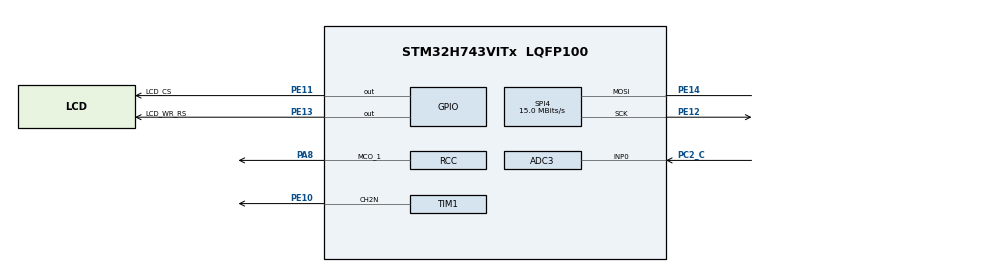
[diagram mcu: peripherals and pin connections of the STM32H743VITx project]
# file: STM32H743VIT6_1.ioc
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ADC3.Channel-0\#ChannelRegularConversion=ADC_CHANNEL_0
ADC3.NbrOfConversionFlag=1
ADC3.OffsetNumber-0\#ChannelRegularConversion=ADC_OFFSET_NONE
ADC3.OffsetSignedSaturation-0\#ChannelRegularConversion=DISABLE
ADC3.Rank-0\#ChannelRegularConversion=1
ADC3.SamplingTime-0\#ChannelRegularConversion=ADC_SAMPLETIME_1CYCLE_5
CORTEX_M7.default_mode_Activation=1
Mcu.Family=STM32H7
Mcu.Name=STM32H743VITx
Mcu.Package=LQFP100
NVIC.PriorityGroup=NVIC_PRIORITYGROUP_4
PA8.Mode=Clock-out-1
PA8.Signal=RCC_MCO_1
PC14-OSC32_IN\ (OSC32_IN).Mode=LSE-External-Oscillator
PC14-OSC32_IN\ (OSC32_IN).Signal=RCC_OSC32_IN
PC15-OSC32_OUT\ (OSC32_OUT).Mode=LSE-External-Oscillator
PC15-OSC32_OUT\ (OSC32_OUT).Signal=RCC_OSC32_OUT
PC2_C.Mode=IN0-Single-Ended
PC2_C.Signal=ADC3_INP0
PE10.Mode=PWM Generation2 CH2N
PE10.Signal=TIM1_CH2N
PE11.GPIO_Label=LCD_CS
PE11.Signal=GPIO_Output
PE12.Mode=Simplex_Bidirectional_Master
PE12.Signal=SPI4_SCK
PE13.GPIO_Label=LCD_WR_RS
PE13.Signal=GPIO_Output
PE14.Mode=Simplex_Bidirectional_Master
PE14.Signal=SPI4_MOSI
PH0-OSC_IN\ (PH0).Mode=HSE-External-Oscillator
PH0-OSC_IN\ (PH0).Signal=RCC_OSC_IN
PH1-OSC_OUT\ (PH1).Mode=HSE-External-Oscillator
PH1-OSC_OUT\ (PH1).Signal=RCC_OSC_OUT
ProjectManager.HeapSize=0x200
ProjectManager.StackSize=0x400
ProjectManager.TargetToolchain=STM32CubeIDE
RCC.ADCFreq_Value=80000000
RCC.APB1Freq_Value=120000000
RCC.APB2Freq_Value=120000000
RCC.APB3Freq_Value=120000000
RCC.APB4Freq_Value=120000000
RCC.CortexFreq_Value=480000000
RCC.D1PPRE=RCC_APB3_DIV2
RCC.D2PPRE1=RCC_APB1_DIV2
RCC.D2PPRE2=RCC_APB2_DIV2
RCC.D3PPRE=RCC_APB4_DIV2
RCC.DIVM1=4
RCC.DIVM2=4
RCC.DIVN1=60
RCC.DIVN2=10
RCC.DIVQ1=5
RCC.HCLKFreq_Value=240000000
RCC.HPRE=RCC_HCLK_DIV2
RCC.PLL2FRACN=0
RCC.PLL3FRACN=0
RCC.PLLFRACN=0
RCC.SYSCLKFreq_VALUE=480000000
RCC.SYSCLKSource=RCC_SYSCLKSOURCE_PLLCLK
RCC.USBFreq_Value=192000000
SPI4.BaudRatePrescaler=SPI_BAUDRATEPRESCALER_8
SPI4.CalculateBaudRate=15.0 MBits/s
SPI4.DataSize=SPI_DATASIZE_8BIT
SPI4.Direction=SPI_DIRECTION_1LINE
SPI4.Mode=SPI_MODE_MASTER
SPI4.VirtualType=VM_MASTER
TIM1.Channel-PWM\ Generation2\ CH2N=TIM_CHANNEL_2
VP_MEMORYMAP_VS_MEMORYMAP.Mode=CurAppReg
board=custom

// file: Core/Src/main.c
/* USER CODE BEGIN Header */
/**
  ******************************************************************************
  * @file           : main.c
  * @brief          : Main program body
  ******************************************************************************
  * @attention
  *
  * Copyright (c) 2026 STMicroelectronics.
  * All rights reserved.
  *
  * This software is licensed under terms that can be found in the LICENSE file
  * in the root directory of this software component.
  * If no LICENSE file comes with this software, it is provided AS-IS.
  *
  ******************************************************************************
  */
/* USER CODE END Header */
#include "main.h"

/* USER CODE BEGIN Includes */
#include "st7735.h"
/* USER CODE END Includes */

ADC_HandleTypeDef hadc3;

SPI_HandleTypeDef hspi4;

TIM_HandleTypeDef htim1;

void SystemClock_Config(void);
static void MPU_Config(void);
static void MX_GPIO_Init(void);
static void MX_ADC3_Init(void);
static void MX_SPI4_Init(void);
static void MX_TIM1_Init(void);

int main(void)
{

  /* MPU Configuration--------------------------------------------------------*/
  MPU_Config();

  /* MCU Configuration--------------------------------------------------------*/

  /* Reset of all peripherals, Initializes the Flash interface and the Systick. */
  HAL_Init();

  /* Configure the system clock */
  SystemClock_Config();

  /* Initialize all configured peripherals */
  MX_GPIO_Init();
  MX_ADC3_Init();
  MX_SPI4_Init();
  MX_TIM1_Init();
  /* USER CODE BEGIN 2 */
  ST7735_Init(&hspi4);
  ST7735_FillScreen(ST7735_BLACK);
  ST7735_DrawString(0, 0, "STM32H7 + ST7735", ST7735_WHITE, ST7735_BLACK);
  /* USER CODE END 2 */

  /* Infinite loop */
  while (1)
  {

  }
}

void SystemClock_Config(void)
{
  RCC_OscInitTypeDef RCC_OscInitStruct = {0};
  RCC_ClkInitTypeDef RCC_ClkInitStruct = {0};

  /** Supply configuration update enable
  */
  HAL_PWREx_ConfigSupply(PWR_LDO_SUPPLY);

  /** Configure the main internal regulator output voltage
  */
  __HAL_PWR_VOLTAGESCALING_CONFIG(PWR_REGULATOR_VOLTAGE_SCALE0);

  while(!__HAL_PWR_GET_FLAG(PWR_FLAG_VOSRDY)) {}

  /** Initializes the RCC Oscillators according to the specified parameters
  * in the RCC_OscInitTypeDef structure.
  */
  RCC_OscInitStruct.OscillatorType = RCC_OSCILLATORTYPE_HSI;
  RCC_OscInitStruct.HSIState = RCC_HSI_DIV1;
  RCC_OscInitStruct.HSICalibrationValue = RCC_HSICALIBRATION_DEFAULT;
  RCC_OscInitStruct.PLL.PLLState = RCC_PLL_ON;
  RCC_OscInitStruct.PLL.PLLSource = RCC_PLLSOURCE_HSI;
  RCC_OscInitStruct.PLL.PLLM = 4;
  RCC_OscInitStruct.PLL.PLLN = 60;
  RCC_OscInitStruct.PLL.PLLP = 2;
  RCC_OscInitStruct.PLL.PLLQ = 5;
  RCC_OscInitStruct.PLL.PLLR = 2;
  RCC_OscInitStruct.PLL.PLLRGE = RCC_PLL1VCIRANGE_3;
  RCC_OscInitStruct.PLL.PLLVCOSEL = RCC_PLL1VCOWIDE;
  RCC_OscInitStruct.PLL.PLLFRACN = 0;
  if (HAL_RCC_OscConfig(&RCC_OscInitStruct) != HAL_OK)
  {
    Error_Handler();
  }

  /** Initializes the CPU, AHB and APB buses clocks
  */
  RCC_ClkInitStruct.ClockType = RCC_CLOCKTYPE_HCLK|RCC_CLOCKTYPE_SYSCLK
                              |RCC_CLOCKTYPE_PCLK1|RCC_CLOCKTYPE_PCLK2
                              |RCC_CLOCKTYPE_D3PCLK1|RCC_CLOCKTYPE_D1PCLK1;
  RCC_ClkInitStruct.SYSCLKSource = RCC_SYSCLKSOURCE_PLLCLK;
  RCC_ClkInitStruct.SYSCLKDivider = RCC_SYSCLK_DIV1;
  RCC_ClkInitStruct.AHBCLKDivider = RCC_HCLK_DIV2;
  RCC_ClkInitStruct.APB3CLKDivider = RCC_APB3_DIV2;
  RCC_ClkInitStruct.APB1CLKDivider = RCC_APB1_DIV2;
  RCC_ClkInitStruct.APB2CLKDivider = RCC_APB2_DIV2;
  RCC_ClkInitStruct.APB4CLKDivider = RCC_APB4_DIV2;

  if (HAL_RCC_ClockConfig(&RCC_ClkInitStruct, FLASH_LATENCY_4) != HAL_OK)
  {
    Error_Handler();
  }
  HAL_RCC_MCOConfig(RCC_MCO1, RCC_MCO1SOURCE_HSI, RCC_MCODIV_1);
}

static void MX_ADC3_Init(void)
{

  ADC_ChannelConfTypeDef sConfig = {0};

  /** Common config
  */
  hadc3.Instance = ADC3;
  hadc3.Init.ClockPrescaler = ADC_CLOCK_ASYNC_DIV1;
  hadc3.Init.Resolution = ADC_RESOLUTION_16B;
  hadc3.Init.ScanConvMode = ADC_SCAN_DISABLE;
  hadc3.Init.EOCSelection = ADC_EOC_SINGLE_CONV;
  hadc3.Init.LowPowerAutoWait = DISABLE;
  hadc3.Init.ContinuousConvMode = DISABLE;
  hadc3.Init.NbrOfConversion = 1;
  hadc3.Init.DiscontinuousConvMode = DISABLE;
  hadc3.Init.ExternalTrigConv = ADC_SOFTWARE_START;
  hadc3.Init.ExternalTrigConvEdge = ADC_EXTERNALTRIGCONVEDGE_NONE;
  hadc3.Init.ConversionDataManagement = ADC_CONVERSIONDATA_DR;
  hadc3.Init.Overrun = ADC_OVR_DATA_PRESERVED;
  hadc3.Init.LeftBitShift = ADC_LEFTBITSHIFT_NONE;
  hadc3.Init.OversamplingMode = DISABLE;
  hadc3.Init.Oversampling.Ratio = 1;
  if (HAL_ADC_Init(&hadc3) != HAL_OK)
  {
    Error_Handler();
  }

  /** Configure Regular Channel
  */
  sConfig.Channel = ADC_CHANNEL_0;
  sConfig.Rank = ADC_REGULAR_RANK_1;
  sConfig.SamplingTime = ADC_SAMPLETIME_1CYCLE_5;
  sConfig.SingleDiff = ADC_SINGLE_ENDED;
  sConfig.OffsetNumber = ADC_OFFSET_NONE;
  sConfig.Offset = 0;
  sConfig.OffsetSignedSaturation = DISABLE;
  if (HAL_ADC_ConfigChannel(&hadc3, &sConfig) != HAL_OK)
  {
    Error_Handler();
  }

}

static void MX_SPI4_Init(void)
{

  /* SPI4 parameter configuration*/
  hspi4.Instance = SPI4;
  hspi4.Init.Mode = SPI_MODE_MASTER;
  hspi4.Init.Direction = SPI_DIRECTION_1LINE;
  hspi4.Init.DataSize = SPI_DATASIZE_8BIT;
  hspi4.Init.CLKPolarity = SPI_POLARITY_LOW;
  hspi4.Init.CLKPhase = SPI_PHASE_1EDGE;
  hspi4.Init.NSS = SPI_NSS_SOFT;
  hspi4.Init.BaudRatePrescaler = SPI_BAUDRATEPRESCALER_8;
  hspi4.Init.FirstBit = SPI_FIRSTBIT_MSB;
  hspi4.Init.TIMode = SPI_TIMODE_DISABLE;
  hspi4.Init.CRCCalculation = SPI_CRCCALCULATION_DISABLE;
  hspi4.Init.CRCPolynomial = 0x0;
  hspi4.Init.NSSPMode = SPI_NSS_PULSE_ENABLE;
  hspi4.Init.NSSPolarity = SPI_NSS_POLARITY_LOW;
  hspi4.Init.FifoThreshold = SPI_FIFO_THRESHOLD_01DATA;
  hspi4.Init.TxCRCInitializationPattern = SPI_CRC_INITIALIZATION_ALL_ZERO_PATTERN;
  hspi4.Init.RxCRCInitializationPattern = SPI_CRC_INITIALIZATION_ALL_ZERO_PATTERN;
  hspi4.Init.MasterSSIdleness = SPI_MASTER_SS_IDLENESS_00CYCLE;
  hspi4.Init.MasterInterDataIdleness = SPI_MASTER_INTERDATA_IDLENESS_00CYCLE;
  hspi4.Init.MasterReceiverAutoSusp = SPI_MASTER_RX_AUTOSUSP_DISABLE;
  hspi4.Init.MasterKeepIOState = SPI_MASTER_KEEP_IO_STATE_DISABLE;
  hspi4.Init.IOSwap = SPI_IO_SWAP_DISABLE;
  if (HAL_SPI_Init(&hspi4) != HAL_OK)
  {
    Error_Handler();
  }

}

static void MX_TIM1_Init(void)
{

  TIM_MasterConfigTypeDef sMasterConfig = {0};
  TIM_OC_InitTypeDef sConfigOC = {0};
  TIM_BreakDeadTimeConfigTypeDef sBreakDeadTimeConfig = {0};

  htim1.Instance = TIM1;
  htim1.Init.Prescaler = 0;
  htim1.Init.CounterMode = TIM_COUNTERMODE_UP;
  htim1.Init.Period = 65535;
  htim1.Init.ClockDivision = TIM_CLOCKDIVISION_DIV1;
  htim1.Init.RepetitionCounter = 0;
  htim1.Init.AutoReloadPreload = TIM_AUTORELOAD_PRELOAD_DISABLE;
  if (HAL_TIM_PWM_Init(&htim1) != HAL_OK)
  {
    Error_Handler();
  }
  sMasterConfig.MasterOutputTrigger = TIM_TRGO_RESET;
  sMasterConfig.MasterOutputTrigger2 = TIM_TRGO2_RESET;
  sMasterConfig.MasterSlaveMode = TIM_MASTERSLAVEMODE_DISABLE;
  if (HAL_TIMEx_MasterConfigSynchronization(&htim1, &sMasterConfig) != HAL_OK)
  {
    Error_Handler();
  }
  sConfigOC.OCMode = TIM_OCMODE_PWM1;
  sConfigOC.Pulse = 0;
  sConfigOC.OCPolarity = TIM_OCPOLARITY_HIGH;
  sConfigOC.OCNPolarity = TIM_OCNPOLARITY_HIGH;
  sConfigOC.OCFastMode = TIM_OCFAST_DISABLE;
  sConfigOC.OCIdleState = TIM_OCIDLESTATE_RESET;
  sConfigOC.OCNIdleState = TIM_OCNIDLESTATE_RESET;
  if (HAL_TIM_PWM_ConfigChannel(&htim1, &sConfigOC, TIM_CHANNEL_2) != HAL_OK)
  {
    Error_Handler();
  }
  sBreakDeadTimeConfig.OffStateRunMode = TIM_OSSR_DISABLE;
  sBreakDeadTimeConfig.OffStateIDLEMode = TIM_OSSI_DISABLE;
  sBreakDeadTimeConfig.LockLevel = TIM_LOCKLEVEL_OFF;
  sBreakDeadTimeConfig.DeadTime = 0;
  sBreakDeadTimeConfig.BreakState = TIM_BREAK_DISABLE;
  sBreakDeadTimeConfig.BreakPolarity = TIM_BREAKPOLARITY_HIGH;
  sBreakDeadTimeConfig.BreakFilter = 0;
  sBreakDeadTimeConfig.Break2State = TIM_BREAK2_DISABLE;
  sBreakDeadTimeConfig.Break2Polarity = TIM_BREAK2POLARITY_HIGH;
  sBreakDeadTimeConfig.Break2Filter = 0;
  sBreakDeadTimeConfig.AutomaticOutput = TIM_AUTOMATICOUTPUT_DISABLE;
  if (HAL_TIMEx_ConfigBreakDeadTime(&htim1, &sBreakDeadTimeConfig) != HAL_OK)
  {
    Error_Handler();
  }
  HAL_TIM_MspPostInit(&htim1);

}

static void MX_GPIO_Init(void)
{
  GPIO_InitTypeDef GPIO_InitStruct = {0};

  /* GPIO Ports Clock Enable */
  __HAL_RCC_GPIOC_CLK_ENABLE();
  __HAL_RCC_GPIOH_CLK_ENABLE();
  __HAL_RCC_GPIOE_CLK_ENABLE();
  __HAL_RCC_GPIOA_CLK_ENABLE();

  /*Configure GPIO pin Output Level */
  HAL_GPIO_WritePin(GPIOE, LCD_BL_Pin|LCD_CS_Pin|LCD_DC_Pin, GPIO_PIN_RESET);

  /*Configure GPIO pins : LCD_BL_Pin LCD_CS_Pin LCD_DC_Pin */
  GPIO_InitStruct.Pin = LCD_BL_Pin|LCD_CS_Pin|LCD_DC_Pin;
  GPIO_InitStruct.Mode = GPIO_MODE_OUTPUT_PP;
  GPIO_InitStruct.Pull = GPIO_NOPULL;
  GPIO_InitStruct.Speed = GPIO_SPEED_FREQ_LOW;
  HAL_GPIO_Init(GPIOE, &GPIO_InitStruct);

  /* Defaults */
  HAL_GPIO_WritePin(LCD_CS_GPIO_Port, LCD_CS_Pin, GPIO_PIN_SET);   // CS inactive
  HAL_GPIO_WritePin(LCD_BL_GPIO_Port, LCD_BL_Pin, GPIO_PIN_SET);   // backlight ON
  HAL_GPIO_WritePin(LCD_DC_GPIO_Port, LCD_DC_Pin, GPIO_PIN_RESET); // command mode default

  /*Configure GPIO pin : PA8 */
  GPIO_InitStruct.Pin = GPIO_PIN_8;
  GPIO_InitStruct.Mode = GPIO_MODE_AF_PP;
  GPIO_InitStruct.Pull = GPIO_NOPULL;
  GPIO_InitStruct.Speed = GPIO_SPEED_FREQ_LOW;
  GPIO_InitStruct.Alternate = GPIO_AF0_MCO;
  HAL_GPIO_Init(GPIOA, &GPIO_InitStruct);

}

 /* MPU Configuration */

void MPU_Config(void)
{
  MPU_Region_InitTypeDef MPU_InitStruct = {0};

  /* Disables the MPU */
  HAL_MPU_Disable();

  /** Initializes and configures the Region and the memory to be protected
  */
  MPU_InitStruct.Enable = MPU_REGION_ENABLE;
  MPU_InitStruct.Number = MPU_REGION_NUMBER0;
  MPU_InitStruct.BaseAddress = 0x0;
  MPU_InitStruct.Size = MPU_REGION_SIZE_4GB;
  MPU_InitStruct.SubRegionDisable = 0x87;
  MPU_InitStruct.TypeExtField = MPU_TEX_LEVEL0;
  MPU_InitStruct.AccessPermission = MPU_REGION_NO_ACCESS;
  MPU_InitStruct.DisableExec = MPU_INSTRUCTION_ACCESS_DISABLE;
  MPU_InitStruct.IsShareable = MPU_ACCESS_SHAREABLE;
  MPU_InitStruct.IsCacheable = MPU_ACCESS_NOT_CACHEABLE;
  MPU_InitStruct.IsBufferable = MPU_ACCESS_NOT_BUFFERABLE;

  HAL_MPU_ConfigRegion(&MPU_InitStruct);
  /* Enables the MPU */
  HAL_MPU_Enable(MPU_PRIVILEGED_DEFAULT);

}

void Error_Handler(void)
{
  __disable_irq();
  while (1)
  {
  }
}
